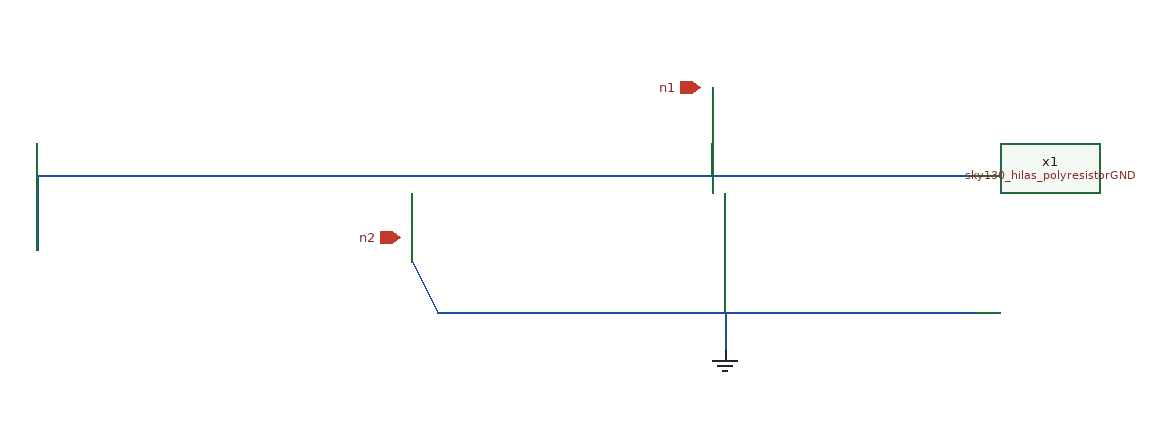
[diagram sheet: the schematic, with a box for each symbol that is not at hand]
v {xschem version=2.9.9 file_version=1.2 }
G {}
K {}
V {}
S {}
E {}
N 310 110 460 110 { lab=#net1}
N 460 110 590 110 { lab=#net1}
N 590 110 720 110 { lab=#net1}
N 310 220 460 220 { lab=GND}
N 460 220 590 220 { lab=GND}
N 610 220 720 220 { lab=GND}
N 590 220 610 220 { lab=GND}
N 520 220 520 250 { lab=GND}
N 510 40 510 110 { lab=#net1}
N 270 180 290 220 { lab=GND}
N 290 220 310 220 { lab=GND}
N -30 110 310 110 { lab=#net1}
N -30 110 -30 170 { lab=#net1}
C {/home/phardytx/share/xschem/xschem_library/devices/gnd.sym} 520 250 0 0 {name=l1 lab=GND}
C {/home/phardytx/share/xschem/xschem_library/devices/iopin.sym} 500 40 0 0 {name=p1 lab=n1}
C {sky130_hilas_polyresistorGND.sym} 120 160 0 0 {name=x1}
C {/home/phardytx/share/xschem/xschem_library/devices/iopin.sym} 260 160 0 0 {name=p2 lab=n2}
